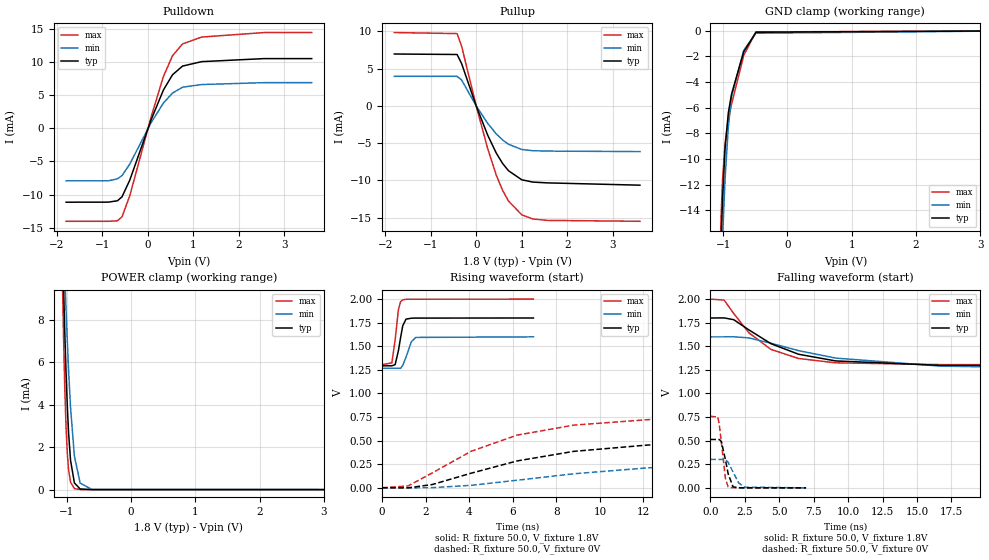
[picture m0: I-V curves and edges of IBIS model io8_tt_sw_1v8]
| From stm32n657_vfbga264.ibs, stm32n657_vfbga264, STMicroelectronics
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[Model]   io8_tt_sw_1v8
Model_type I/O
Polarity   Non-Inverting
Enable   Active-Low
| CAP_THRESHOLD on pad IOTT is "UDTCAPC" :
| Rising=30.0% of vddiov33sw   Falling=70.0% of vddiov33sw
| C_comp min and max val. don't necessarily correlate with the min and max pvt
| but are the smallest and greatest pad capacitance found.
| var   typ   min   max
C_comp   908.89555fF  882.59950fF  931.64250fF
|C_comp_pullup   530.45500fF  521.94000fF  540.51500fF
|C_comp_pulldown   378.44055fF  360.65950fF  391.12750fF
Vinl = 480.0mV
Vinh = 1.4V
Vmeas = 900.0mV   | Reference voltage for timing measurements
Cref  = 50.0pF   | Timing specification test load capacitance value
Rref  = 100.0MOhm   | Timing specification test load resistance value
Vref  = 900.0mV   | Timing specification test load voltage
[Model Spec]
| TIME_THRESHOLD on pin ZIV08SW is "CMOS" :
| Rising=50.0% of vddv08sw   Falling=50.0% of vddv08sw
Vinl 1.07470V 960.70000mV 1.21270V
Vinh 1.54130V 1.38830V 1.71030V
| variable   typ   min   max
[Temperature Range] 25.0 125.0 -40.0
| variable   typ   min   max
[Voltage Range] 1.8V 1.6V 2.0V
| variable   typ   min   max
[POWER Clamp Reference] 1.8V 1.6V 2.0V
| variable   typ   min   max
[GND Clamp Reference] 0V 0V 0V
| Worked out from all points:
|   slope of the pulldown table from 0 to 0.27 V, typ, clamps not added: 56.7 ohm
|   slope of the pullup table from 0 to 0.27 V, typ, clamps not added: 65.2 ohm
|   GND clamp passes 1 mA (typ) near -0.60 V on its own axis
|   POWER clamp passes 1 mA (typ) near -0.93 V on its own axis
|   rising waveform, R_fixture 50.0, V_fixture 1.8V: 20-80 % time 232ps typ, 302ps min, 198ps max; typ from 1.29 V to 1.8 V
|   falling waveform, R_fixture 50.0, V_fixture 1.8V: 20-80 % time 4.44ns typ, 7.1ns min, 3.1ns max; typ from 1.8 V to 1.29 V
|   rising waveform, R_fixture 50.0, V_fixture 0V: 20-80 % time 6.39ns typ, 9.55ns min, 4.89ns max; typ from 0 V to 0.513 V
|   falling waveform, R_fixture 50.0, V_fixture 0V: 20-80 % time 424ps typ, 610ps min, 339ps max; typ from 0.513 V to 0 V
[POWER Clamp]
-1.8V     154.4mA    107.1mA    224.4mA
-1.07V    12.25mA    13.82mA    10.53mA
-1.05V    9.71mA     11.92mA    7.355mA
-1.03V    7.448mA    10.14mA    4.813mA
-1.01V    5.5mA      8.482mA    2.941mA
-990mV    3.897mA    6.962mA    1.686mA
-970mV    2.647mA    5.596mA    919.8uA
-940mV    1.378mA    3.864mA    349.1uA
-880mV    312.8uA    1.572mA    46.17uA
-790mV    28.9uA     304.1uA    2.138uA
-610mV    229.1nA    8.315uA    10.43nA
3.6V      0A         0A         0A
[GND Clamp]
-1.8V     -979.1mA   -715mA     -1.119A
-1.06V    -21.86mA   -24.46mA   -19.94mA
-1.05V    -19.75mA   -22.55mA   -17.72mA
-1.04V    -17.84mA   -20.78mA   -15.8mA
-1.03V    -16.13mA   -19.14mA   -14.17mA
-1.01V    -13.21mA   -16.21mA   -11.65mA
-970mV    -9.146mA   -11.54mA   -8.745mA
-920mV    -6.416mA   -7.546mA   -6.96mA
-870mV    -4.947mA   -5.127mA   -5.728mA
-680mV    -1.634mA   -1.519mA   -1.917mA
-490mV    -108.8uA   -186.7uA   -87.16uA
3.6V      16.54nA    423.1nA    6.356nA
| variable   typ   min   max
[Pullup Reference] 1.8V 1.6V 2.0V
| variable   typ   min   max
[Pulldown Reference] 0V 0V 0V
[Pullup]
-1.8V     6.976mA    3.977mA    9.855mA
-420mV    6.911mA    3.977mA    9.716mA
-320mV    5.677mA    3.476mA    8.007mA
0V        14.9pA     1.112nA    1.1pA
250mV     -3.883mA   -2.32mA    -5.669mA
440mV     -6.317mA   -3.742mA   -9.27mA
580mV     -7.719mA   -4.565mA   -11.33mA
710mV     -8.698mA   -5.144mA   -12.77mA
1V        -9.907mA   -5.841mA   -14.61mA
1.24V     -10.22mA   -6.007mA   -15.17mA
1.56V     -10.33mA   -6.062mA   -15.37mA
3.6V      -10.64mA   -6.13mA    -15.49mA
[Pulldown]
-1.8V     -11.16mA   -7.922mA   -14.05mA
-870mV    -11.15mA   -7.921mA   -14.05mA
-670mV    -10.94mA   -7.621mA   -13.98mA
-570mV    -10.34mA   -7.128mA   -13.35mA
-400mV    -7.819mA   -5.39mA    -10.19mA
70mV      1.323mA    886.5uA    1.768mA
340mV     5.822mA    3.845mA    7.866mA
540mV     8.126mA    5.356mA    11.01mA
760mV     9.438mA    6.239mA    12.79mA
1.18V     10.11mA    6.643mA    13.83mA
2.55V     10.57mA    6.932mA    14.51mA
3.6V      10.57mA    6.932mA    14.51mA
[Ramp]
dV/dt_r 307.61485mV/6.3881ns 180.74492mV/9.31502ns 455.17717mV/4.89317ns
dV/dt_f 304.15245mV/4.44156ns 199.78963mV/7.06444ns 416.82618mV/3.09919ns
R_load = 50.0
| Removed startup time: 0s 0s 0s  .
| Removed end time: 6.95ns.
[Rising Waveform]
R_fixture   = 50.0
V_fixture   = 1.8V
V_fixture_min = 1.6V
V_fixture_max = 2.0V
0s        1.293V     1.267V     1.305V
450ps     1.293V     1.267V     1.324V
600ps     1.305V     1.267V     1.567V
750ps     1.453V     1.267V     1.888V
850ps     1.591V     1.266V     1.973V
950ps     1.718V     1.297V     1.992V
1.1ns     1.788V     1.386V     1.998V
1.35ns    1.798V     1.55V      1.999V
1.55ns    1.799V     1.594V     1.999V
6.95ns    1.8V       1.6V       2V
| Removed startup time: 0s 0s 0s  .
| Removed end time: 74.9ns.
[Falling Waveform]
R_fixture   = 50.0
V_fixture   = 1.8V
V_fixture_min = 1.6V
V_fixture_max = 2.0V
0s        1.8V       1.6V       2V
1ns       1.801V     1.6V       1.99V
1.7ns     1.782V     1.601V     1.848V
2.8ns     1.674V     1.589V     1.643V
4.4ns     1.528V     1.533V     1.467V
6.4ns     1.416V     1.454V     1.371V
9.1ns     1.345V     1.375V     1.325V
16.7ns    1.298V     1.29V      1.306V
25ns      1.293V     1.271V     1.305V
74.9ns    1.293V     1.267V     1.305V
| Removed startup time: 0s 0s 0s  .
| Removed end time: 74.9ns.
[Rising Waveform]
R_fixture   = 50.0
V_fixture   = 0V
V_fixture_min = 0V
V_fixture_max = 0V
0s        85.69nV    1.021uV    176nV
1.2ns     -369.9uV   -1.248mV   19.28mV
2.3ns     33.73mV    696.6uV    156.8mV
4.1ns     154.9mV    25.85mV    387.9mV
6.2ns     284.3mV    79.7mV     557.9mV
8.8ns     385.8mV    148mV      664.1mV
12.2ns    453mV      211mV      721.8mV
16.7ns    489.7mV    255.9mV    747.5mV
25ns      508.4mV    287.6mV    757.4mV
74.9ns    512.7mV    301.2mV    758.6mV
| Removed startup time: 0s 0s 0s  .
| Removed end time: 6.95ns.
[Falling Waveform]
R_fixture   = 50.0
V_fixture   = 0V
V_fixture_min = 0V
V_fixture_max = 0V
0s        512.7mV    301.3mV    758.6mV
550ps     512.7mV    301.2mV    749.8mV
650ps     512.8mV    301.2mV    672.6mV
800ps     492mV      301.3mV    487.8mV
1.1ns     297.3mV    301.8mV    98.93mV
1.3ns     146.4mV    269.9mV    8.424mV
1.65ns    11.12mV    168mV      854.8uV
2.05ns    834uV      54.23mV    421.2uV
2.45ns    396.7uV    7.443mV    268.7uV
6.95ns    47.32uV    69.72uV    27.99uV
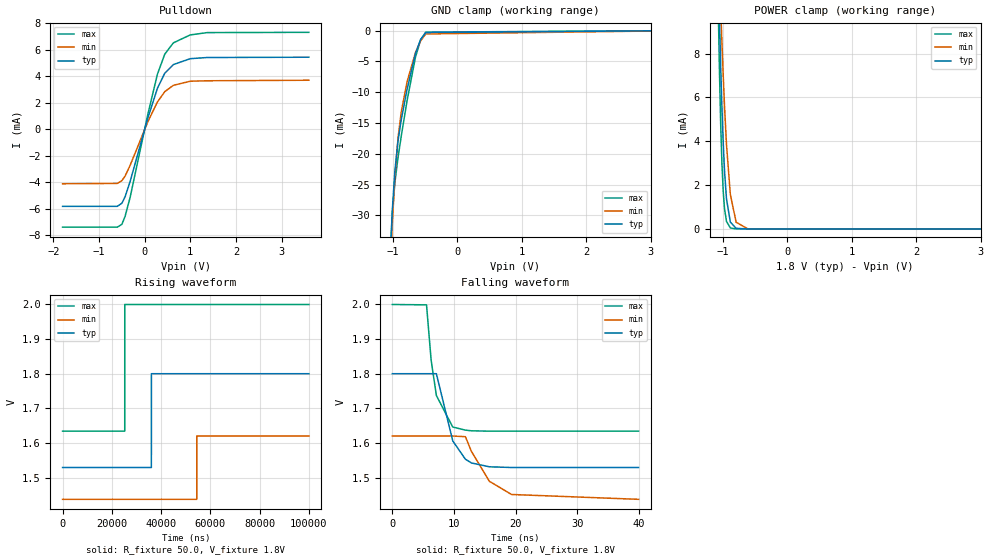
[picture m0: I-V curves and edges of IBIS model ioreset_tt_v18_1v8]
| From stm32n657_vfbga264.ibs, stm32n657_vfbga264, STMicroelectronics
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[Model]   ioreset_tt_v18_1v8
Model_type I/O_open_drain
Polarity   Inverting
Enable   Active-Low
| CAP_THRESHOLD on pad IOTT is "UDTCAPC" :
| Rising=30.0% of vddiov33m   Falling=70.0% of vddiov33m
| C_comp min and max val. don't necessarily correlate with the min and max pvt
| but are the smallest and greatest pad capacitance found.
| var   typ   min   max
C_comp   912.69500fF  900.60500fF  952.10500fF
|C_comp_pulldown   912.69500fF  900.60500fF  952.10500fF
Vinl = 486.0mV
Vinh = 1.4V
Vmeas = 900.0mV   | Reference voltage for timing measurements
Cref  = 1.0pF   | Timing specification test load capacitance value
Rref  = 1.0kOhm   | Timing specification test load resistance value
Vref  = 1.8V   | Timing specification test load voltage
[Model Spec]
| TIME_THRESHOLD on pin ZIV18M is "CMOS" :
| Rising=50.0% of vddiov18m   Falling=50.0% of vddiov18m
Vinl 1.02470V 917.70000mV 1.33070V
Vinh 1.27830V 1.14430V 1.42630V
| variable   typ   min   max
[Temperature Range] 25.0 125.0 -40.0
| variable   typ   min   max
[Voltage Range] 1.8V 1.62V 2.0V
| variable   typ   min   max
[POWER Clamp Reference] 1.8V 1.62V 2.0V
| variable   typ   min   max
[GND Clamp Reference] 0V 0V 0V
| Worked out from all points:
|   slope of the pulldown table from 0 to 0.27 V, typ, clamps not added: 89.7 ohm
|   GND clamp passes 1 mA (typ) near -0.55 V on its own axis
|   POWER clamp passes 1 mA (typ) near -0.93 V on its own axis
|   rising waveform, R_fixture 50.0, V_fixture 1.8V: 20-80 % time 6ns typ, 6ns min, 6.01ns max; typ from 1.53 V to 1.8 V
|   falling waveform, R_fixture 50.0, V_fixture 1.8V: 20-80 % time 2.51ns typ, 4.09ns min, 1.72ns max; typ from 1.8 V to 1.53 V
[POWER Clamp]
-1.8V     154.4mA    107.2mA    224.4mA
-1.07V    12.25mA    13.82mA    10.53mA
-1.05V    9.71mA     11.92mA    7.356mA
-1.03V    7.448mA    10.14mA    4.813mA
-1.01V    5.5mA      8.482mA    2.941mA
-990mV    3.897mA    6.962mA    1.686mA
-970mV    2.647mA    5.596mA    919.8uA
-940mV    1.378mA    3.864mA    349.1uA
-880mV    312.8uA    1.572mA    46.17uA
-790mV    28.9uA     304.1uA    2.137uA
-610mV    228.9nA    8.34uA     9.186nA
3.6V      0A         0A         0A
[GND Clamp]
-1.8V     -1.214A    -1.184A    -1.231A
-1.05V    -39.79mA   -42.62mA   -39.23mA
-1.04V    -36.67mA   -39.42mA   -36.31mA
-1.01V    -29.34mA   -31.51mA   -29.9mA
-970mV    -22.87mA   -23.89mA   -24.77mA
-920mV    -17.88mA   -17.44mA   -20.59mA
-870mV    -14.46mA   -13.19mA   -17.11mA
-780mV    -9.523mA   -8.313mA   -11.37mA
-650mV    -3.739mA   -3.576mA   -4.322mA
-570mV    -1.448mA   -1.663mA   -1.528mA
-490mV    -323uA     -554.4uA   -258.6uA
3.6V      31.22nA    420.8nA    50.78nA
| variable   typ   min   max
[Pullup Reference] 1.8V 1.62V 2.0V
| variable   typ   min   max
[Pulldown Reference] 0V 0V 0V
[Pulldown]
-1.8V     -5.824mA   -4.118mA   -7.395mA
-600mV    -5.822mA   -4.092mA   -7.395mA
-500mV    -5.588mA   -3.88mA    -7.181mA
-430mV    -5.099mA   -3.541mA   -6.581mA
-320mV    -3.954mA   -2.733mA   -5.154mA
70mV      855.1uA    572.9uA    1.142mA
280mV     3.1mA      2.064mA    4.167mA
440mV     4.23mA     2.84mA     5.67mA
630mV     4.886mA    3.319mA    6.528mA
1V        5.33mA     3.628mA    7.125mA
1.37V     5.418mA    3.661mA    7.299mA
3.6V      5.44mA     3.702mA    7.32mA
[Ramp]
dV/dt_r 162.63487mV/123.88797ps 109.86281mV/159.29437ps 218.9817mV/106.65524ps
dV/dt_f 162.63316mV/2.51032ns 109.85497mV/4.08986ns 219.43864mV/1.72176ns
R_load = 50.0
| Removed startup time: 0s 0s 0s  .
| Removed end time: 99.99us.
[Rising Waveform]
R_fixture   = 50.0
V_fixture   = 1.8V
V_fixture_min = 1.62V
V_fixture_max = 2.0V
0s        1.529V     1.437V     1.634V
25.23us   1.529V     1.437V     1.634V
25.24us   1.529V     1.437V     1.999V
25.25us   1.529V     1.437V     2V
36.05us   1.529V     1.437V     2V
36.06us   1.8V       1.437V     2V
54.49us   1.8V       1.437V     2V
54.5us    1.8V       1.62V      2V
54.51us   1.8V       1.62V      2V
99.99us   1.8V       1.62V      2V
| Removed startup time: 0s 0s 0s  .
| Removed end time: 39.95ns.
[Falling Waveform]
R_fixture   = 50.0
V_fixture   = 1.8V
V_fixture_min = 1.62V
V_fixture_max = 2.0V
0s        1.8V       1.62V      2V
5.55ns    1.8V       1.62V      1.999V
6.3ns     1.8V       1.62V      1.839V
7.15ns    1.8V       1.62V      1.737V
9.8ns     1.606V     1.62V      1.646V
11.85ns   1.553V     1.618V     1.637V
12.85ns   1.542V     1.575V     1.635V
15.75ns   1.531V     1.489V     1.634V
19.35ns   1.529V     1.451V     1.634V
39.95ns   1.529V     1.437V     1.634V
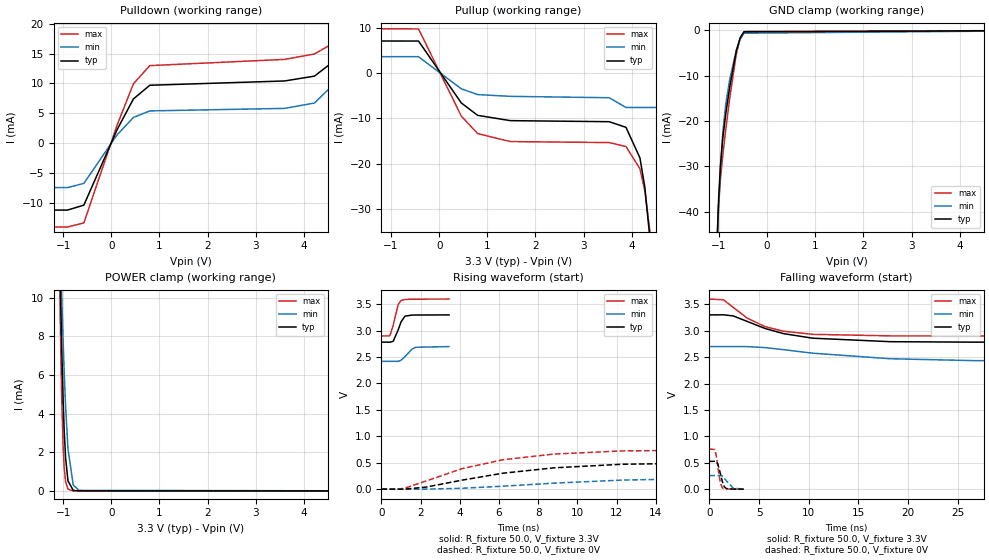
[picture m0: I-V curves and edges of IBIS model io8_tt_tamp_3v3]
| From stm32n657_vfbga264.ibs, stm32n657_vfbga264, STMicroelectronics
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[Model]   io8_tt_tamp_3v3
Model_type I/O
Polarity   Non-Inverting
Enable   Active-Low
| CAP_THRESHOLD on pad IOTT is "UDTCAPC" :
| Rising=30.0% of vddiov33m   Falling=70.0% of vddiov33m
| C_comp min and max val. don't necessarily correlate with the min and max pvt
| but are the smallest and greatest pad capacitance found.
| var   typ   min   max
C_comp   1.35170pF  1.34924pF  1.36636pF
|C_comp_pullup   655.12000fF  637.52000fF  682.06000fF
|C_comp_pulldown   696.58000fF  711.72155fF  684.29500fF
Vinl = 810.0mV
Vinh = 2.52V
Vmeas = 1.65V   | Reference voltage for timing measurements
Cref  = 50.0pF   | Timing specification test load capacitance value
Rref  = 100.0MOhm   | Timing specification test load resistance value
Vref  = 1.65V   | Timing specification test load voltage
[Model Spec]
| TIME_THRESHOLD on pin ZIV08SW is "CMOS" :
| Rising=50.0% of vddv08sw   Falling=50.0% of vddv08sw
Vinl 1.08570V 868.70000mV 1.21270V
Vinh 1.55630V 1.26330V 1.71030V
| variable   typ   min   max
[Temperature Range] 25.0 125.0 -40.0
| variable   typ   min   max
[Voltage Range] 3.3V 2.7V 3.6V
| variable   typ   min   max
[POWER Clamp Reference] 3.3V 2.7V 3.6V
| variable   typ   min   max
[GND Clamp Reference] 0V 0V 0V
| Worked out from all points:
|   slope of the pulldown table from 0 to 0.495 V, typ, clamps not added: 64.8 ohm
|   slope of the pullup table from 0 to 0.495 V, typ, clamps not added: 71.9 ohm
|   GND clamp passes 1 mA (typ) near -0.53 V on its own axis
|   POWER clamp passes 1 mA (typ) near -0.93 V on its own axis
|   rising waveform, R_fixture 50.0, V_fixture 3.3V: 20-80 % time 313ps typ, 428ps min, 267ps max; typ from 2.78 V to 3.3 V
|   falling waveform, R_fixture 50.0, V_fixture 3.3V: 20-80 % time 5.67ns typ, 10.1ns min, 3.96ns max; typ from 3.3 V to 2.78 V
|   rising waveform, R_fixture 50.0, V_fixture 0V: 20-80 % time 6.29ns typ, 9.92ns min, 4.95ns max; typ from 0 V to 0.528 V
|   falling waveform, R_fixture 50.0, V_fixture 0V: 20-80 % time 429ps typ, 636ps min, 355ps max; typ from 0.528 V to 0.001 V
[POWER Clamp]
-3.3V     1.379A     322.5mA    2.015A
-1.07V    12.25mA    13.82mA    10.53mA
-1.06V    10.95mA    12.86mA    8.872mA
-1.05V    9.711mA    11.93mA    7.358mA
-1.03V    7.449mA    10.14mA    4.816mA
-1V       4.656mA    7.706mA    2.245mA
-980mV    3.23mA     6.261mA    1.254mA
-950mV    1.729mA    4.399mA    486.6uA
-900mV    522.4uA    2.171mA    92.53uA
-790mV    29.26uA    304.7uA    3.016uA
-670mV    1.36uA     28.12uA    546.2nA
6.6V      0A         0A         0A
[GND Clamp]
-3.3V     -3.798A    -3.78A     -3.808A
-1.05V    -50.4mA    -53.25mA   -50.41mA
-1.04V    -46.61mA   -49.27mA   -46.93mA
-1.01V    -37.76mA   -39.56mA   -39.23mA
-970mV    -29.92mA   -30.3mA    -32.87mA
-920mV    -23.7mA    -22.48mA   -27.44mA
-860mV    -18.48mA   -16.4mA    -21.94mA
-780mV    -12.71mA   -11mA      -15.18mA
-640mV    -4.528mA   -4.378mA   -5.198mA
-560mV    -1.666mA   -1.973mA   -1.722mA
-480mV    -339.7uA   -626.5uA   -256.2uA
6.6V      260.7nA    5.333uA    309nA
| variable   typ   min   max
[Pullup Reference] 3.3V 2.7V 3.6V
| variable   typ   min   max
[Pulldown Reference] 0V 0V 0V
[Pullup]
-3.3V     7.046mA    3.582mA    9.739mA
-430mV    7.02mA     3.582mA    9.691mA
460mV     -6.603mA   -3.484mA   -9.498mA
800mV     -9.321mA   -4.753mA   -13.34mA
1.48V     -10.48mA   -5.137mA   -15.08mA
3.53V     -10.71mA   -5.441mA   -15.3mA
3.88V     -11.95mA   -7.58mA    -16.17mA
4.17V     -18.68mA   -7.58mA    -21.07mA
4.27V     -25.02mA   -7.58mA    -25.81mA
4.38V     -36.68mA   -7.58mA    -35.12mA
4.39V     -38mA      -7.58mA    -36.28mA
6.6V      -46.18mA   -7.58mA    -116.1mA
[Pulldown]
-3.3V     -11.21mA   -7.442mA   -14.05mA
-910mV    -11.21mA   -7.442mA   -14.05mA
-570mV    -10.38mA   -6.74mA    -13.35mA
120mV     2.252mA    1.384mA    2.997mA
460mV     7.403mA    4.305mA    9.944mA
800mV     9.692mA    5.397mA    12.98mA
3.6V      10.41mA    5.82mA     14.02mA
4.22V     11.22mA    6.712mA    14.93mA
4.56V     13.32mA    9.4mA      16.49mA
4.9V      20.4mA     17.95mA    22.55mA
5.19V     37.09mA    36.8mA     37.38mA
6.6V      250mA      253.9mA    245.2mA
[Ramp]
dV/dt_r 316.76783mV/6.28723ns 154.94129mV/9.78637ns 455.99387mV/4.9461ns
dV/dt_f 310.43038mV/5.675ns 168.20758mV/10.08142ns 419.63796mV/3.95687ns
R_load = 50.0
| Removed startup time: 0s 0s 0s  .
| Removed end time: 3.45ns.
[Rising Waveform]
R_fixture   = 50.0
V_fixture   = 3.3V
V_fixture_min = 2.7V
V_fixture_max = 3.6V
0s        2.783V     2.42V      2.901V
400ps     2.783V     2.42V      2.901V
450ps     2.783V     2.42V      2.925V
600ps     2.8V       2.42V      3.103V
850ps     3.011V     2.419V     3.493V
1ns       3.167V     2.44V      3.572V
1.2ns     3.275V     2.509V     3.591V
1.55ns    3.295V     2.647V     3.596V
1.75ns    3.297V     2.686V     3.597V
3.45ns    3.299V     2.699V     3.599V
| Removed startup time: 0s 0s 0s  .
| Removed end time: 59.9ns.
[Falling Waveform]
R_fixture   = 50.0
V_fixture   = 3.3V
V_fixture_min = 2.7V
V_fixture_max = 3.6V
0s        3.3V       2.7V       3.6V
1.4ns     3.302V     2.701V     3.587V
2.4ns     3.281V     2.701V     3.443V
3.8ns     3.177V     2.7V       3.24V
5.6ns     3.043V     2.681V     3.078V
7.5ns     2.944V     2.641V     2.99V
10.4ns    2.859V     2.575V     2.932V
18.2ns    2.793V     2.47V      2.903V
26.7ns    2.784V     2.434V     2.901V
59.9ns    2.783V     2.42V      2.901V
| Removed startup time: 0s 0s 0s  .
| Removed end time: 69.9ns.
[Rising Waveform]
R_fixture   = 50.0
V_fixture   = 0V
V_fixture_min = 0V
V_fixture_max = 0V
0s        940.4nV    5.04uV     1.138uV
900ps     -1.301mV   -417.4uV   -1.255mV
1.2ns     -830.6uV   -704.3uV   18.35mV
2.3ns     39.26mV    -23.03uV   155.9mV
4.1ns     168.8mV    15.17mV    386.3mV
6.2ns     301.1mV    55.21mV    556mV
8.8ns     402.8mV    112.6mV    663.4mV
12.3ns    471.1mV    171.2mV    723.7mV
23.3ns    522.5mV    240.4mV    758.1mV
69.9ns    527.9mV    258.2mV    760mV
| Removed startup time: 0s 0s 0s  .
| Removed end time: 3.45ns.
[Falling Waveform]
R_fixture   = 50.0
V_fixture   = 0V
V_fixture_min = 0V
V_fixture_max = 0V
0s        527.9mV    258.3mV    760mV
550ps     527.9mV    258.3mV    751.3mV
700ps     528.7mV    258.3mV    625mV
850ps     478.7mV    258.3mV    429.5mV
1.1ns     301.1mV    258.4mV    122.1mV
1.3ns     148mV      247.8mV    25.5mV
1.5ns     48.29mV    210mV      7.57mV
1.7ns     12.2mV     160.5mV    3.751mV
2.4ns     1.684mV    19.45mV    1.336mV
3.45ns    641.2uV    853.3uV    537.3uV
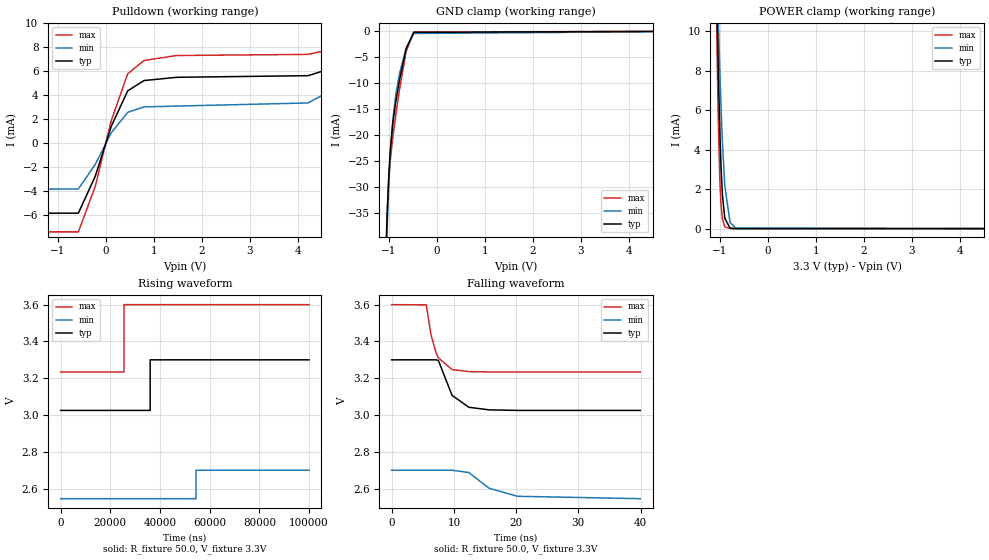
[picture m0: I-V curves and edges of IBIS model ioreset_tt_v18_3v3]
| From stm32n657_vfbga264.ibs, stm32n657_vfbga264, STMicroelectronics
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[Model]   ioreset_tt_v18_3v3
Model_type I/O_open_drain
Polarity   Inverting
Enable   Active-Low
| CAP_THRESHOLD on pad IOTT is "UDTCAPC" :
| Rising=30.0% of vddiov33m   Falling=70.0% of vddiov33m
| C_comp min and max val. don't necessarily correlate with the min and max pvt
| but are the smallest and greatest pad capacitance found.
| var   typ   min   max
C_comp   921.72500fF  908.97000fF  929.51500fF
|C_comp_pulldown   921.72500fF  908.97000fF  929.51500fF
Vinl = 810.0mV
Vinh = 2.52V
Vmeas = 1.65V   | Reference voltage for timing measurements
Cref  = 1.0pF   | Timing specification test load capacitance value
Rref  = 1.0kOhm   | Timing specification test load resistance value
Vref  = 3.3V   | Timing specification test load voltage
[Model Spec]
| TIME_THRESHOLD on pin ZIV18M is "CMOS" :
| Rising=50.0% of vddiov18m   Falling=50.0% of vddiov18m
Vinl 1.16070V 1.04270V 1.17170V
Vinh 1.29530V 1.04830V 1.42630V
| variable   typ   min   max
[Temperature Range] 25.0 125.0 -40.0
| variable   typ   min   max
[Voltage Range] 3.3V 2.7V 3.6V
| variable   typ   min   max
[POWER Clamp Reference] 3.3V 2.7V 3.6V
| variable   typ   min   max
[GND Clamp Reference] 0V 0V 0V
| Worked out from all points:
|   slope of the pulldown table from 0 to 0.495 V, typ, clamps not added: 111 ohm
|   GND clamp passes 1 mA (typ) near -0.55 V on its own axis
|   POWER clamp passes 1 mA (typ) near -0.93 V on its own axis
|   rising waveform, R_fixture 50.0, V_fixture 3.3V: 20-80 % time 6ns typ, 6.01ns min, 6ns max; typ from 3.02 V to 3.3 V
|   falling waveform, R_fixture 50.0, V_fixture 3.3V: 20-80 % time 2.49ns typ, 4.51ns min, 1.72ns max; typ from 3.3 V to 3.02 V
[POWER Clamp]
-3.3V     1.357A     323mA      2.003A
-1.07V    12.25mA    13.82mA    10.53mA
-1.06V    10.95mA    12.86mA    8.872mA
-1.05V    9.711mA    11.93mA    7.358mA
-1.03V    7.449mA    10.14mA    4.816mA
-1V       4.655mA    7.706mA    2.245mA
-980mV    3.23mA     6.261mA    1.254mA
-950mV    1.729mA    4.4mA      486.6uA
-900mV    522.4uA    2.172mA    92.62uA
-790mV    29.31uA    305.5uA    3.197uA
-670mV    1.437uA    28.91uA    776.1nA
6.6V      0A         0A         0A
[GND Clamp]
-3.3V     -3.764A    -3.734A    -3.781A
-1.05V    -39.8mA    -42.49mA   -39.23mA
-1.04V    -36.68mA   -39.29mA   -36.31mA
-1.03V    -33.94mA   -36.4mA    -33.83mA
-1V       -27.44mA   -29.24mA   -28.34mA
-970mV    -22.87mA   -23.8mA    -24.77mA
-920mV    -17.89mA   -17.37mA   -20.59mA
-860mV    -13.87mA   -12.47mA   -16.45mA
-780mV    -9.526mA   -8.276mA   -11.37mA
-640mV    -3.391mA   -3.28mA    -3.892mA
-480mV    -253.3uA   -467.6uA   -190.9uA
6.6V      130.7nA    555.7nA    230.9nA
| variable   typ   min   max
[Pullup Reference] 3.3V 2.7V 3.6V
| variable   typ   min   max
[Pulldown Reference] 0V 0V 0V
[Pulldown]
-3.3V     -5.854mA   -3.866mA   -7.395mA
-570mV    -5.828mA   -3.813mA   -7.39mA
-220mV    -2.775mA   -1.779mA   -3.632mA
120mV     1.45mA     891.2uA    1.929mA
460mV     4.369mA    2.574mA    5.798mA
800mV     5.224mA    3.027mA    6.895mA
1.48V     5.493mA    3.095mA    7.31mA
4.22V     5.63mA     3.356mA    7.403mA
4.56V     6.053mA    4.09mA     7.697mA
4.9V      7.61mA     6.6mA      8.825mA
5.1V      9.95mA     10.18mA    10.57mA
6.6V      85.37mA    95.63mA    72.69mA
[Ramp]
dV/dt_r 164.49923mV/121.71059ps 92.27683mV/165.50906ps 219.52725mV/104.78434ps
dV/dt_f 164.92056mV/2.48691ns 92.89558mV/4.51111ns 219.52684mV/1.72143ns
R_load = 50.0
| Removed startup time: 0s 0s 0s  .
| Removed end time: 99.99us.
[Rising Waveform]
R_fixture   = 50.0
V_fixture   = 3.3V
V_fixture_min = 2.7V
V_fixture_max = 3.6V
0s        3.025V     2.545V     3.234V
25.5us    3.025V     2.545V     3.234V
25.51us   3.025V     2.545V     3.6V
25.52us   3.025V     2.545V     3.6V
36.05us   3.025V     2.545V     3.6V
36.06us   3.3V       2.545V     3.6V
54.49us   3.3V       2.545V     3.6V
54.5us    3.3V       2.7V       3.6V
54.51us   3.3V       2.7V       3.6V
99.99us   3.3V       2.7V       3.6V
| Removed startup time: 0s 0s 0s  .
| Removed end time: 39.95ns.
[Falling Waveform]
R_fixture   = 50.0
V_fixture   = 3.3V
V_fixture_min = 2.7V
V_fixture_max = 3.6V
0s        3.3V       2.7V       3.6V
5.55ns    3.3V       2.7V       3.599V
6.3ns     3.3V       2.7V       3.439V
7.15ns    3.3V       2.7V       3.336V
7.5ns     3.297V     2.7V       3.311V
9.7ns     3.107V     2.7V       3.247V
12.4ns    3.042V     2.687V     3.236V
15.65ns   3.028V     2.602V     3.234V
20.2ns    3.025V     2.558V     3.234V
39.95ns   3.025V     2.545V     3.234V
